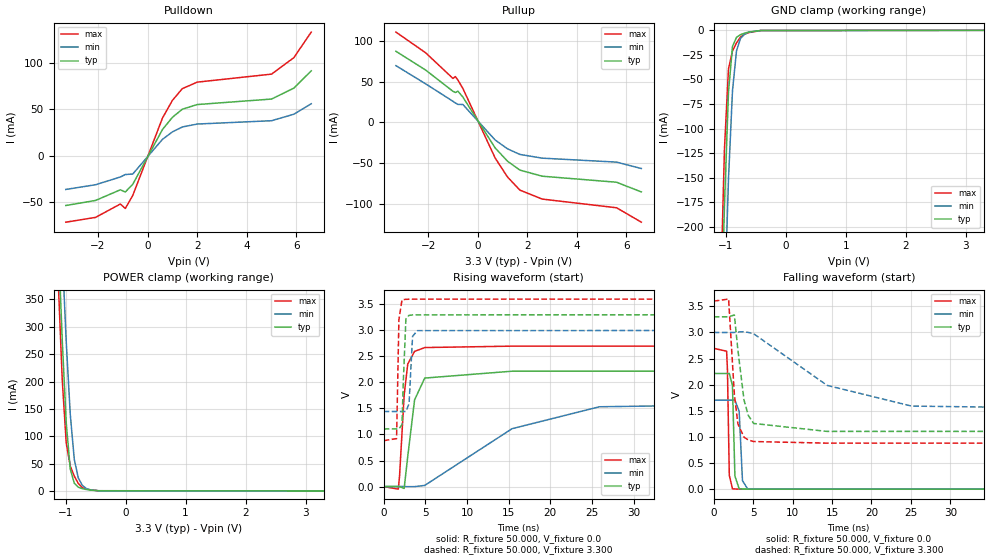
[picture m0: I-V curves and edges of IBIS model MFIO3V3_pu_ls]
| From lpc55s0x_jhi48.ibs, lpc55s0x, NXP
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|   Model MFIO3V3_pu_ls
[Model] MFIO3V3_pu_ls
Model_type I/O
Polarity   Non-Inverting
Enable   Active-Low
Vinl =  0.990V
Vinh =  2.310V
Vmeas =  1.650V
Cref =  0.0F
Rref =  100.000
Vref =  0.0V
C_comp   1.906pF   1.877pF   1.925pF
C_comp_pullup   1.139pF   1.112pF   1.144pF
C_comp_pulldown   0.643pF   0.602pF   0.649pF
[Model Spec]
Vinh   2.310V   2.100V   2.520V
Vinl   0.990V   0.900V   1.080V
Vmeas   1.650V   1.500V   1.800V
Vref   0.0V   0.0V   0.0V
Cref   0.0F   0.0F   0.0F
Rref   100.000   100.000   100.000
[Temperature Range]   25.000   0.125k   -40.000
[Voltage Range]   3.300V   3.000V   3.600V
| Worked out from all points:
|   slope of the pulldown table from 0 to 0.495 V, typ, clamps not added: 20.7 ohm
|   slope of the pullup table from 0 to 0.495 V, typ, clamps not added: 21.4 ohm
|   GND clamp passes 1 mA (typ) near -0.55 V on its own axis
|   POWER clamp passes 1 mA (typ) near -0.54 V on its own axis
|   rising waveform, R_fixture 50.000, V_fixture 0.0: 20-80 % time 1.05ns typ, 11.9ns min, 674ps max; typ from 0.001 V to 2.21 V
|   rising waveform, R_fixture 50.000, V_fixture 3.300: 20-80 % time 179ps typ, 230ps min, 146ps max; typ from 1.11 V to 3.3 V
|   falling waveform, R_fixture 50.000, V_fixture 0.0: 20-80 % time 203ps typ, 278ps min, 162ps max; typ from 2.21 V to 0.001 V
|   falling waveform, R_fixture 50.000, V_fixture 3.300: 20-80 % time 1.14ns typ, 11.2ns min, 744ps max; typ from 3.3 V to 1.11 V
[Pulldown]
|Voltage   I(typ)   I(min)   I(max)
-3.3V     -53.7mA    -36.43mA   -71.67mA
-2.1V     -48.29mA   -31.37mA   -66.51mA
-1.1V     -36.82mA   -23.05mA   -52.1mA
-900mV    -39.2mA    -20.39mA   -56.91mA
-600mV    -30.96mA   -19.83mA   -42.97mA
600mV     28.07mA    17.5mA     40.4mA
1V        41.17mA    25.53mA    59.41mA
1.4V      49.87mA    30.79mA    72.04mA
2V        54.93mA    33.94mA    79.03mA
5V        60.84mA    37.53mA    87.68mA
5.9V      72.62mA    44.52mA    105.4mA
6.6V      91.19mA    55.78mA    132.9mA
[Pullup]
|Voltage   I(typ)   I(min)   I(max)
-3.3V     87.16mA    69.54mA    110.7mA
-2.1V     64.12mA    47.22mA    85.31mA
-1V       38.1mA     25.85mA    53.88mA
-900mV    36.64mA    23.75mA    56.16mA
-800mV    38.25mA    22.02mA    51.93mA
-600mV    31.06mA    21.93mA    41.58mA
700mV     -31.25mA   -21.55mA   -43.56mA
1.2V      -47.6mA    -32.42mA   -66.97mA
1.7V      -58.52mA   -39.3mA    -83.05mA
2.6V      -66.01mA   -43.88mA   -94.06mA
5.6V      -73.4mA    -48.74mA   -104.7mA
6.6V      -85.32mA   -56.6mA    -122.4mA
[GND_clamp]
|Voltage   I(typ)   I(min)   I(max)
-3.3V     -7.222A    -7.177A    -7.278A
-1.089V   -337.2mA   -440.9mA   -274.2mA
-1.022V   -178.3mA   -284.2mA   -121.1mA
-955mV    -63.12mA   -151.7mA   -39.33mA
-888mV    -16.39mA   -61.39mA   -20.98mA
-821mV    -7.132mA   -20.89mA   -12.74mA
-754mV    -4.331mA   -8.209mA   -6.777mA
-687mV    -2.86mA    -3.948mA   -3.925mA
-620mV    -1.791mA   -1.946mA   -2.423mA
-419mV    -178.1uA   -190.3uA   -219.1uA
3.3V      0A         0A         0A
[POWER_clamp]
|Voltage   I(typ)   I(min)   I(max)
-3.3V     8.016A     7.986A     8.074A
-1.122V   463.7mA    614.3mA    385mA
-1.055V   276.3mA    434.9mA    203.9mA
-988mV    124mA      272.3mA    87.13mA
-921mV    39.96mA    140.1mA    45.6mA
-854mV    14.17mA    57.77mA    27.03mA
-787mV    6.855mA    23.75mA    13.68mA
-720mV    4.075mA    10.22mA    6.123mA
-653mV    2.616mA    4.368mA    3.615mA
-586mV    1.55mA     1.867mA    2.107mA
-452mV    281.1uA    359.9uA    338.7uA
3.3V      0A         0A         0A
[Ramp]
| variable   typ   min   max
dV/dt_r   1.329/1.048n   1.022/11.881n   1.617/0.670n
dV/dt_f   1.316/1.133n   0.935/11.179n   1.631/0.744n
R_load = 50.000
[Rising Waveform]
R_fixture= 50.000
V_fixture= 0.0
V_fixture_min= 0.0
V_fixture_max= 0.0
|time   V(typ)   V(min)   V(max)
0s        869.8uV    949.2uV    842.8uV
1.76ns    883.1uV    948.8uV    -50.04mV
1.91ns    1.009mV    949.1uV    208mV
2.46ns    -36.02mV   1.012mV    1.752V
2.89ns    574.4mV    -2.122mV   2.352V
3.71ns    1.664V     -1.354mV   2.595V
4.93ns    2.083V     22.11mV    2.669V
15.41ns   2.215V     1.111V     2.696V
25.89ns   2.215V     1.532V     2.696V
100ns     2.215V     1.704V     2.696V
[Rising Waveform]
R_fixture= 50.000
V_fixture= 3.300
V_fixture_min= 3.000
V_fixture_max= 3.600
|time   V(typ)   V(min)   V(max)
0s        1.106V     1.442V     881.7mV
1.55ns    1.106V     1.442V     920.7mV
1.83ns    1.106V     1.442V     3.201V
2.2ns     1.19V      1.442V     3.584V
2.36ns    2.014V     1.442V     3.591V
2.67ns    3.219V     1.441V     3.595V
3.05ns    3.288V     1.591V     3.597V
3.47ns    3.295V     2.885V     3.598V
4.05ns    3.297V     2.994V     3.599V
100ns     3.3V       3V         3.6V
[Falling Waveform]
R_fixture= 50.000
V_fixture= 0.0
V_fixture_min= 0.0
V_fixture_max= 0.0
|time   V(typ)   V(min)   V(max)
0s        2.215V     1.704V     2.696V
1.63ns    2.215V     1.704V     2.641V
1.73ns    2.215V     1.704V     2.3V
1.97ns    2.216V     1.704V     265.9mV
2.37ns    1.988V     1.704V     8.752mV
2.68ns    252.6mV    1.704V     4.211mV
3.22ns    8.138mV    1.493V     2.448mV
3.64ns    3.966mV    165.1mV    1.883mV
4.28ns    2.4mV      8.68mV     1.408mV
100ns     869.8uV    949.4uV    842.8uV
[Falling Waveform]
R_fixture= 50.000
V_fixture= 3.300
V_fixture_min= 3.000
V_fixture_max= 3.600
|time   V(typ)   V(min)   V(max)
0s        3.3V       3V         3.6V
1.88ns    3.3V       3V         3.639V
2.61ns    3.334V     3V         1.817V
3.06ns    2.664V     3.008V     1.251V
3.83ns    1.711V     3.015V     996.5mV
4.37ns    1.414V     3.001V     943.5mV
5.06ns    1.258V     2.975V     912.3mV
14.38ns   1.106V     1.987V     881.7mV
25.08ns   1.106V     1.591V     881.7mV
100ns     1.106V     1.442V     881.7mV
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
